VERSION 5.7 ;
  NOWIREEXTENSIONATPIN ON ;
  DIVIDERCHAR "/" ;
  BUSBITCHARS "[]" ;
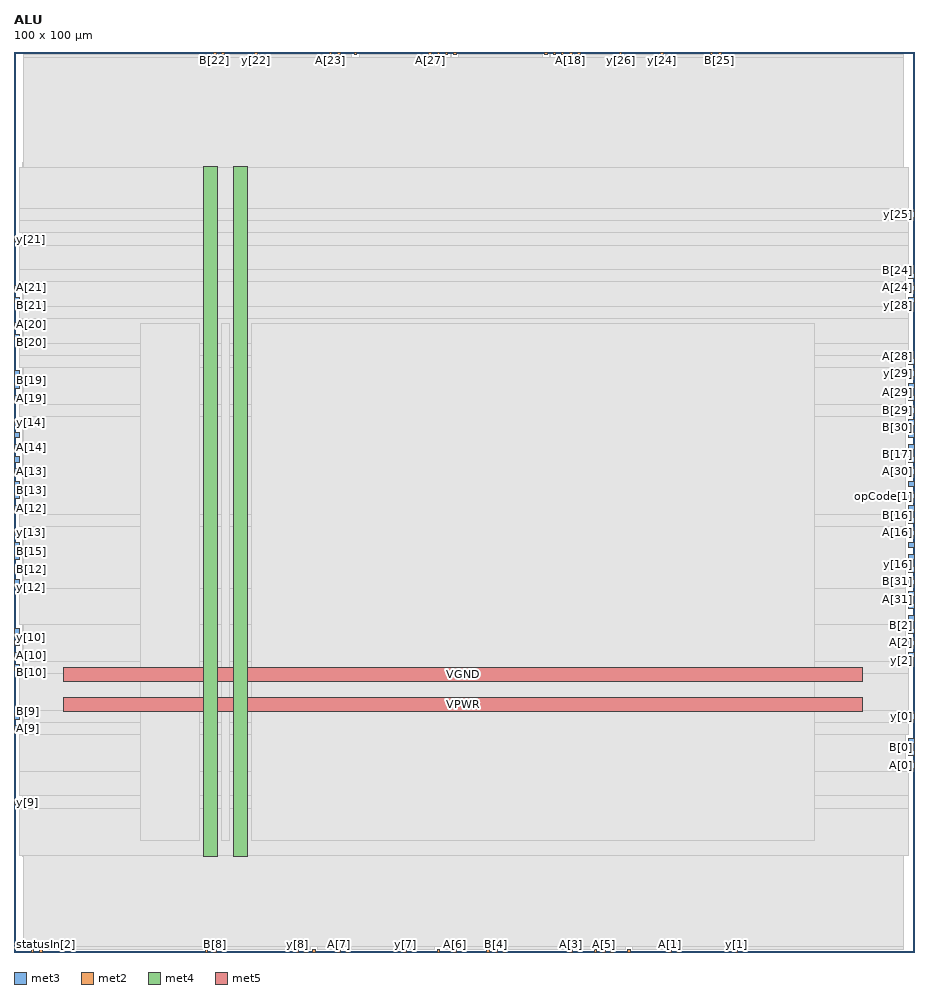
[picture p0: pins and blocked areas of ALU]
MACRO ALU
  CLASS BLOCK ;
  FOREIGN ALU ;
  ORIGIN 0.000 0.000 ;
  SIZE 100.000 BY 100.000 ;
  PIN A[0]
    DIRECTION INPUT ;
    USE SIGNAL ;
    ANTENNAGATEAREA 0.213000 ;
    PORT
      LAYER met3 ;
        RECT 99.400 20.440 100.000 21.040 ;
    END
  END A[0]
  PIN A[10]
    DIRECTION INPUT ;
    USE SIGNAL ;
    ANTENNAGATEAREA 0.213000 ;
    PORT
      LAYER met3 ;
        RECT 0.000 32.680 0.600 33.280 ;
    END
  END A[10]
  PIN A[11]
    DIRECTION INPUT ;
    USE SIGNAL ;
    ANTENNAGATEAREA 0.213000 ;
    PORT
      LAYER met2 ;
        RECT 32.290 0.000 32.570 0.280 ;
    END
  END A[11]
  PIN A[12]
    DIRECTION INPUT ;
    USE SIGNAL ;
    ANTENNAGATEAREA 0.213000 ;
    PORT
      LAYER met3 ;
        RECT 0.000 49.000 0.600 49.600 ;
    END
  END A[12]
  PIN A[13]
    DIRECTION INPUT ;
    USE SIGNAL ;
    ANTENNAGATEAREA 0.213000 ;
    PORT
      LAYER met3 ;
        RECT 0.000 53.080 0.600 53.680 ;
    END
  END A[13]
  PIN A[14]
    DIRECTION INPUT ;
    USE SIGNAL ;
    ANTENNAGATEAREA 0.213000 ;
    PORT
      LAYER met3 ;
        RECT 0.000 55.800 0.600 56.400 ;
    END
  END A[14]
  PIN A[15]
    DIRECTION INPUT ;
    USE SIGNAL ;
    ANTENNAGATEAREA 0.213000 ;
    PORT
      LAYER met3 ;
        RECT 0.000 44.920 0.600 45.520 ;
    END
  END A[15]
  PIN A[16]
    DIRECTION INPUT ;
    USE SIGNAL ;
    ANTENNAGATEAREA 0.213000 ;
    PORT
      LAYER met3 ;
        RECT 99.400 46.280 100.000 46.880 ;
    END
  END A[16]
  PIN A[17]
    DIRECTION INPUT ;
    USE SIGNAL ;
    ANTENNAGATEAREA 0.213000 ;
    PORT
      LAYER met3 ;
        RECT 99.400 57.160 100.000 57.760 ;
    END
  END A[17]
  PIN A[18]
    DIRECTION INPUT ;
    USE SIGNAL ;
    ANTENNAGATEAREA 0.213000 ;
    PORT
      LAYER met2 ;
        RECT 61.730 99.720 62.010 100.000 ;
    END
  END A[18]
  PIN A[19]
    DIRECTION INPUT ;
    USE SIGNAL ;
    ANTENNAGATEAREA 0.213000 ;
    PORT
      LAYER met3 ;
        RECT 0.000 61.240 0.600 61.840 ;
    END
  END A[19]
  PIN A[1]
    DIRECTION INPUT ;
    USE SIGNAL ;
    ANTENNAGATEAREA 0.213000 ;
    PORT
      LAYER met2 ;
        RECT 72.770 0.000 73.050 0.280 ;
    END
  END A[1]
  PIN A[20]
    DIRECTION INPUT ;
    USE SIGNAL ;
    ANTENNAGATEAREA 0.213000 ;
    PORT
      LAYER met3 ;
        RECT 0.000 69.400 0.600 70.000 ;
    END
  END A[20]
  PIN A[21]
    DIRECTION INPUT ;
    USE SIGNAL ;
    ANTENNAGATEAREA 0.213000 ;
    PORT
      LAYER met3 ;
        RECT 0.000 73.480 0.600 74.080 ;
    END
  END A[21]
  PIN A[22]
    DIRECTION INPUT ;
    USE SIGNAL ;
    ANTENNAGATEAREA 0.213000 ;
    PORT
      LAYER met2 ;
        RECT 23.090 99.720 23.370 100.000 ;
    END
  END A[22]
  PIN A[23]
    DIRECTION INPUT ;
    USE SIGNAL ;
    ANTENNAGATEAREA 0.213000 ;
    PORT
      LAYER met2 ;
        RECT 35.050 99.720 35.330 100.000 ;
    END
  END A[23]
  PIN A[24]
    DIRECTION INPUT ;
    USE SIGNAL ;
    ANTENNAGATEAREA 0.213000 ;
    PORT
      LAYER met3 ;
        RECT 99.400 73.480 100.000 74.080 ;
    END
  END A[24]
  PIN A[25]
    DIRECTION INPUT ;
    USE SIGNAL ;
    ANTENNAGATEAREA 0.213000 ;
    PORT
      LAYER met2 ;
        RECT 77.370 99.720 77.650 100.000 ;
    END
  END A[25]
  PIN A[26]
    DIRECTION INPUT ;
    USE SIGNAL ;
    ANTENNAGATEAREA 0.213000 ;
    PORT
      LAYER met2 ;
        RECT 58.970 99.720 59.250 100.000 ;
    END
  END A[26]
  PIN A[27]
    DIRECTION INPUT ;
    USE SIGNAL ;
    ANTENNAGATEAREA 0.213000 ;
    PORT
      LAYER met2 ;
        RECT 46.090 99.720 46.370 100.000 ;
    END
  END A[27]
  PIN A[28]
    DIRECTION INPUT ;
    USE SIGNAL ;
    ANTENNAGATEAREA 0.213000 ;
    PORT
      LAYER met3 ;
        RECT 99.400 65.320 100.000 65.920 ;
    END
  END A[28]
  PIN A[29]
    DIRECTION INPUT ;
    USE SIGNAL ;
    ANTENNAGATEAREA 0.213000 ;
    PORT
      LAYER met3 ;
        RECT 99.400 61.240 100.000 61.840 ;
    END
  END A[29]
  PIN A[2]
    DIRECTION INPUT ;
    USE SIGNAL ;
    ANTENNAGATEAREA 0.213000 ;
    PORT
      LAYER met3 ;
        RECT 99.400 34.040 100.000 34.640 ;
    END
  END A[2]
  PIN A[30]
    DIRECTION INPUT ;
    USE SIGNAL ;
    ANTENNAGATEAREA 0.213000 ;
    PORT
      LAYER met3 ;
        RECT 99.400 53.080 100.000 53.680 ;
    END
  END A[30]
  PIN A[31]
    DIRECTION INPUT ;
    USE SIGNAL ;
    ANTENNAGATEAREA 0.213000 ;
    PORT
      LAYER met3 ;
        RECT 99.400 39.480 100.000 40.080 ;
    END
  END A[31]
  PIN A[3]
    DIRECTION INPUT ;
    USE SIGNAL ;
    ANTENNAGATEAREA 0.213000 ;
    PORT
      LAYER met2 ;
        RECT 61.730 0.000 62.010 0.280 ;
    END
  END A[3]
  PIN A[4]
    DIRECTION INPUT ;
    USE SIGNAL ;
    ANTENNAGATEAREA 0.213000 ;
    PORT
      LAYER met2 ;
        RECT 52.530 0.000 52.810 0.280 ;
    END
  END A[4]
  PIN A[5]
    DIRECTION INPUT ;
    USE SIGNAL ;
    ANTENNAGATEAREA 0.213000 ;
    PORT
      LAYER met2 ;
        RECT 65.410 0.000 65.690 0.280 ;
    END
  END A[5]
  PIN A[6]
    DIRECTION INPUT ;
    USE SIGNAL ;
    ANTENNAGATEAREA 0.213000 ;
    PORT
      LAYER met2 ;
        RECT 48.850 0.000 49.130 0.280 ;
    END
  END A[6]
  PIN A[7]
    DIRECTION INPUT ;
    USE SIGNAL ;
    ANTENNAGATEAREA 0.213000 ;
    PORT
      LAYER met2 ;
        RECT 35.970 0.000 36.250 0.280 ;
    END
  END A[7]
  PIN A[8]
    DIRECTION INPUT ;
    USE SIGNAL ;
    ANTENNAGATEAREA 0.213000 ;
    PORT
      LAYER met2 ;
        RECT 21.250 0.000 21.530 0.280 ;
    END
  END A[8]
  PIN A[9]
    DIRECTION INPUT ;
    USE SIGNAL ;
    ANTENNAGATEAREA 0.213000 ;
    PORT
      LAYER met3 ;
        RECT 0.000 24.520 0.600 25.120 ;
    END
  END A[9]
  PIN B[0]
    DIRECTION INPUT ;
    USE SIGNAL ;
    ANTENNAGATEAREA 0.213000 ;
    PORT
      LAYER met3 ;
        RECT 99.400 21.800 100.000 22.400 ;
    END
  END B[0]
  PIN B[10]
    DIRECTION INPUT ;
    USE SIGNAL ;
    ANTENNAGATEAREA 0.213000 ;
    PORT
      LAYER met3 ;
        RECT 0.000 31.320 0.600 31.920 ;
    END
  END B[10]
  PIN B[11]
    DIRECTION INPUT ;
    USE SIGNAL ;
    ANTENNAGATEAREA 0.213000 ;
    PORT
      LAYER met2 ;
        RECT 33.210 0.000 33.490 0.280 ;
    END
  END B[11]
  PIN B[12]
    DIRECTION INPUT ;
    USE SIGNAL ;
    ANTENNAGATEAREA 0.213000 ;
    PORT
      LAYER met3 ;
        RECT 0.000 42.200 0.600 42.800 ;
    END
  END B[12]
  PIN B[13]
    DIRECTION INPUT ;
    USE SIGNAL ;
    ANTENNAGATEAREA 0.213000 ;
    PORT
      LAYER met3 ;
        RECT 0.000 50.360 0.600 50.960 ;
    END
  END B[13]
  PIN B[14]
    DIRECTION INPUT ;
    USE SIGNAL ;
    ANTENNAGATEAREA 0.213000 ;
    PORT
      LAYER met3 ;
        RECT 0.000 54.440 0.600 55.040 ;
    END
  END B[14]
  PIN B[15]
    DIRECTION INPUT ;
    USE SIGNAL ;
    ANTENNAGATEAREA 0.213000 ;
    PORT
      LAYER met3 ;
        RECT 0.000 43.560 0.600 44.160 ;
    END
  END B[15]
  PIN B[16]
    DIRECTION INPUT ;
    USE SIGNAL ;
    ANTENNAGATEAREA 0.213000 ;
    PORT
      LAYER met3 ;
        RECT 99.400 47.640 100.000 48.240 ;
    END
  END B[16]
  PIN B[17]
    DIRECTION INPUT ;
    USE SIGNAL ;
    ANTENNAGATEAREA 0.213000 ;
    PORT
      LAYER met3 ;
        RECT 99.400 54.440 100.000 55.040 ;
    END
  END B[17]
  PIN B[18]
    DIRECTION INPUT ;
    USE SIGNAL ;
    ANTENNAGATEAREA 0.213000 ;
    PORT
      LAYER met2 ;
        RECT 60.810 99.720 61.090 100.000 ;
    END
  END B[18]
  PIN B[19]
    DIRECTION INPUT ;
    USE SIGNAL ;
    ANTENNAGATEAREA 0.213000 ;
    PORT
      LAYER met3 ;
        RECT 0.000 62.600 0.600 63.200 ;
    END
  END B[19]
  PIN B[1]
    DIRECTION INPUT ;
    USE SIGNAL ;
    ANTENNAGATEAREA 0.213000 ;
    PORT
      LAYER met2 ;
        RECT 73.690 0.000 73.970 0.280 ;
    END
  END B[1]
  PIN B[20]
    DIRECTION INPUT ;
    USE SIGNAL ;
    ANTENNAGATEAREA 0.213000 ;
    PORT
      LAYER met3 ;
        RECT 0.000 68.040 0.600 68.640 ;
    END
  END B[20]
  PIN B[21]
    DIRECTION INPUT ;
    USE SIGNAL ;
    ANTENNAGATEAREA 0.213000 ;
    PORT
      LAYER met3 ;
        RECT 0.000 72.120 0.600 72.720 ;
    END
  END B[21]
  PIN B[22]
    DIRECTION INPUT ;
    USE SIGNAL ;
    ANTENNAGATEAREA 0.213000 ;
    PORT
      LAYER met2 ;
        RECT 22.170 99.720 22.450 100.000 ;
    END
  END B[22]
  PIN B[23]
    DIRECTION INPUT ;
    USE SIGNAL ;
    ANTENNAGATEAREA 0.213000 ;
    PORT
      LAYER met2 ;
        RECT 35.970 99.720 36.250 100.000 ;
    END
  END B[23]
  PIN B[24]
    DIRECTION INPUT ;
    USE SIGNAL ;
    ANTENNAGATEAREA 0.213000 ;
    PORT
      LAYER met3 ;
        RECT 99.400 74.840 100.000 75.440 ;
    END
  END B[24]
  PIN B[25]
    DIRECTION INPUT ;
    USE SIGNAL ;
    ANTENNAGATEAREA 0.213000 ;
    PORT
      LAYER met2 ;
        RECT 78.290 99.720 78.570 100.000 ;
    END
  END B[25]
  PIN B[26]
    DIRECTION INPUT ;
    USE SIGNAL ;
    ANTENNAGATEAREA 0.213000 ;
    PORT
      LAYER met2 ;
        RECT 59.890 99.720 60.170 100.000 ;
    END
  END B[26]
  PIN B[27]
    DIRECTION INPUT ;
    USE SIGNAL ;
    ANTENNAGATEAREA 0.213000 ;
    PORT
      LAYER met2 ;
        RECT 47.010 99.720 47.290 100.000 ;
    END
  END B[27]
  PIN B[28]
    DIRECTION INPUT ;
    USE SIGNAL ;
    ANTENNAGATEAREA 0.213000 ;
    PORT
      LAYER met3 ;
        RECT 99.400 62.600 100.000 63.200 ;
    END
  END B[28]
  PIN B[29]
    DIRECTION INPUT ;
    USE SIGNAL ;
    ANTENNAGATEAREA 0.213000 ;
    PORT
      LAYER met3 ;
        RECT 99.400 59.880 100.000 60.480 ;
    END
  END B[29]
  PIN B[2]
    DIRECTION INPUT ;
    USE SIGNAL ;
    ANTENNAGATEAREA 0.213000 ;
    PORT
      LAYER met3 ;
        RECT 99.400 35.400 100.000 36.000 ;
    END
  END B[2]
  PIN B[30]
    DIRECTION INPUT ;
    USE SIGNAL ;
    ANTENNAGATEAREA 0.213000 ;
    PORT
      LAYER met3 ;
        RECT 99.400 58.520 100.000 59.120 ;
    END
  END B[30]
  PIN B[31]
    DIRECTION INPUT ;
    USE SIGNAL ;
    ANTENNAGATEAREA 0.213000 ;
    PORT
      LAYER met3 ;
        RECT 99.400 40.840 100.000 41.440 ;
    END
  END B[31]
  PIN B[3]
    DIRECTION INPUT ;
    USE SIGNAL ;
    ANTENNAGATEAREA 0.213000 ;
    PORT
      LAYER met3 ;
        RECT 99.400 36.760 100.000 37.360 ;
    END
  END B[3]
  PIN B[4]
    DIRECTION INPUT ;
    USE SIGNAL ;
    ANTENNAGATEAREA 0.213000 ;
    PORT
      LAYER met2 ;
        RECT 53.450 0.000 53.730 0.280 ;
    END
  END B[4]
  PIN B[5]
    DIRECTION INPUT ;
    USE SIGNAL ;
    ANTENNAGATEAREA 0.213000 ;
    PORT
      LAYER met2 ;
        RECT 66.330 0.000 66.610 0.280 ;
    END
  END B[5]
  PIN B[6]
    DIRECTION INPUT ;
    USE SIGNAL ;
    ANTENNAGATEAREA 0.213000 ;
    PORT
      LAYER met2 ;
        RECT 47.010 0.000 47.290 0.280 ;
    END
  END B[6]
  PIN B[7]
    DIRECTION INPUT ;
    USE SIGNAL ;
    ANTENNAGATEAREA 0.213000 ;
    PORT
      LAYER met2 ;
        RECT 36.890 0.000 37.170 0.280 ;
    END
  END B[7]
  PIN B[8]
    DIRECTION INPUT ;
    USE SIGNAL ;
    ANTENNAGATEAREA 0.213000 ;
    PORT
      LAYER met2 ;
        RECT 22.170 0.000 22.450 0.280 ;
    END
  END B[8]
  PIN B[9]
    DIRECTION INPUT ;
    USE SIGNAL ;
    ANTENNAGATEAREA 0.213000 ;
    PORT
      LAYER met3 ;
        RECT 0.000 25.880 0.600 26.480 ;
    END
  END B[9]
  PIN VGND
    DIRECTION INOUT ;
    USE GROUND ;
    PORT
      LAYER met4 ;
        RECT 24.340 10.640 25.940 87.280 ;
    END
    PORT
      LAYER met5 ;
        RECT 5.520 30.030 94.300 31.630 ;
    END
  END VGND
  PIN VPWR
    DIRECTION INOUT ;
    USE POWER ;
    PORT
      LAYER met4 ;
        RECT 21.040 10.640 22.640 87.280 ;
    END
    PORT
      LAYER met5 ;
        RECT 5.520 26.730 94.300 28.330 ;
    END
  END VPWR
  PIN opCode[0]
    DIRECTION INPUT ;
    USE SIGNAL ;
    ANTENNAGATEAREA 0.213000 ;
    PORT
      LAYER met3 ;
        RECT 99.400 49.000 100.000 49.600 ;
    END
  END opCode[0]
  PIN opCode[1]
    DIRECTION INPUT ;
    USE SIGNAL ;
    ANTENNAGATEAREA 0.213000 ;
    PORT
      LAYER met3 ;
        RECT 99.400 50.360 100.000 50.960 ;
    END
  END opCode[1]
  PIN opCode[2]
    DIRECTION INPUT ;
    USE SIGNAL ;
    ANTENNAGATEAREA 0.213000 ;
    PORT
      LAYER met3 ;
        RECT 99.400 51.720 100.000 52.320 ;
    END
  END opCode[2]
  PIN statusIn[0]
    DIRECTION INPUT ;
    USE SIGNAL ;
    ANTENNAGATEAREA 0.213000 ;
    PORT
      LAYER met3 ;
        RECT 99.400 23.160 100.000 23.760 ;
    END
  END statusIn[0]
  PIN statusIn[1]
    DIRECTION INPUT ;
    USE SIGNAL ;
    PORT
      LAYER met2 ;
        RECT 1.930 0.000 2.210 0.280 ;
    END
  END statusIn[1]
  PIN statusIn[2]
    DIRECTION INPUT ;
    USE SIGNAL ;
    PORT
      LAYER met2 ;
        RECT 2.850 0.000 3.130 0.280 ;
    END
  END statusIn[2]
  PIN statusOut
    DIRECTION OUTPUT ;
    USE SIGNAL ;
    ANTENNADIFFAREA 0.702900 ;
    PORT
      LAYER met3 ;
        RECT 99.400 44.920 100.000 45.520 ;
    END
  END statusOut
  PIN y[0]
    DIRECTION OUTPUT ;
    USE SIGNAL ;
    ANTENNADIFFAREA 0.702900 ;
    PORT
      LAYER met3 ;
        RECT 99.400 25.880 100.000 26.480 ;
    END
  END y[0]
  PIN y[10]
    DIRECTION OUTPUT ;
    USE SIGNAL ;
    ANTENNADIFFAREA 0.702900 ;
    PORT
      LAYER met3 ;
        RECT 0.000 34.040 0.600 34.640 ;
    END
  END y[10]
  PIN y[11]
    DIRECTION OUTPUT ;
    USE SIGNAL ;
    ANTENNADIFFAREA 0.702900 ;
    PORT
      LAYER met3 ;
        RECT 0.000 35.400 0.600 36.000 ;
    END
  END y[11]
  PIN y[12]
    DIRECTION OUTPUT ;
    USE SIGNAL ;
    ANTENNADIFFAREA 0.702900 ;
    PORT
      LAYER met3 ;
        RECT 0.000 40.840 0.600 41.440 ;
    END
  END y[12]
  PIN y[13]
    DIRECTION OUTPUT ;
    USE SIGNAL ;
    ANTENNADIFFAREA 0.702900 ;
    PORT
      LAYER met3 ;
        RECT 0.000 46.280 0.600 46.880 ;
    END
  END y[13]
  PIN y[14]
    DIRECTION OUTPUT ;
    USE SIGNAL ;
    ANTENNADIFFAREA 0.702900 ;
    PORT
      LAYER met3 ;
        RECT 0.000 58.520 0.600 59.120 ;
    END
  END y[14]
  PIN y[15]
    DIRECTION OUTPUT ;
    USE SIGNAL ;
    ANTENNADIFFAREA 0.702900 ;
    PORT
      LAYER met3 ;
        RECT 0.000 51.720 0.600 52.320 ;
    END
  END y[15]
  PIN y[16]
    DIRECTION OUTPUT ;
    USE SIGNAL ;
    ANTENNADIFFAREA 0.702900 ;
    PORT
      LAYER met3 ;
        RECT 99.400 42.200 100.000 42.800 ;
    END
  END y[16]
  PIN y[17]
    DIRECTION OUTPUT ;
    USE SIGNAL ;
    ANTENNADIFFAREA 0.702900 ;
    PORT
      LAYER met2 ;
        RECT 48.850 99.720 49.130 100.000 ;
    END
  END y[17]
  PIN y[18]
    DIRECTION OUTPUT ;
    USE SIGNAL ;
    ANTENNADIFFAREA 0.702900 ;
    PORT
      LAYER met2 ;
        RECT 62.650 99.720 62.930 100.000 ;
    END
  END y[18]
  PIN y[19]
    DIRECTION OUTPUT ;
    USE SIGNAL ;
    ANTENNADIFFAREA 0.702900 ;
    PORT
      LAYER met3 ;
        RECT 0.000 57.160 0.600 57.760 ;
    END
  END y[19]
  PIN y[1]
    DIRECTION OUTPUT ;
    USE SIGNAL ;
    ANTENNADIFFAREA 0.702900 ;
    PORT
      LAYER met2 ;
        RECT 80.130 0.000 80.410 0.280 ;
    END
  END y[1]
  PIN y[20]
    DIRECTION OUTPUT ;
    USE SIGNAL ;
    ANTENNADIFFAREA 0.702900 ;
    PORT
      LAYER met3 ;
        RECT 0.000 63.960 0.600 64.560 ;
    END
  END y[20]
  PIN y[21]
    DIRECTION OUTPUT ;
    USE SIGNAL ;
    ANTENNADIFFAREA 0.702900 ;
    PORT
      LAYER met3 ;
        RECT 0.000 78.920 0.600 79.520 ;
    END
  END y[21]
  PIN y[22]
    DIRECTION OUTPUT ;
    USE SIGNAL ;
    ANTENNADIFFAREA 0.702900 ;
    PORT
      LAYER met2 ;
        RECT 26.770 99.720 27.050 100.000 ;
    END
  END y[22]
  PIN y[23]
    DIRECTION OUTPUT ;
    USE SIGNAL ;
    ANTENNADIFFAREA 0.702900 ;
    PORT
      LAYER met2 ;
        RECT 37.810 99.720 38.090 100.000 ;
    END
  END y[23]
  PIN y[24]
    DIRECTION OUTPUT ;
    USE SIGNAL ;
    ANTENNADIFFAREA 0.702900 ;
    PORT
      LAYER met2 ;
        RECT 71.850 99.720 72.130 100.000 ;
    END
  END y[24]
  PIN y[25]
    DIRECTION OUTPUT ;
    USE SIGNAL ;
    ANTENNADIFFAREA 0.702900 ;
    PORT
      LAYER met3 ;
        RECT 99.400 81.640 100.000 82.240 ;
    END
  END y[25]
  PIN y[26]
    DIRECTION OUTPUT ;
    USE SIGNAL ;
    ANTENNADIFFAREA 0.702900 ;
    PORT
      LAYER met2 ;
        RECT 67.250 99.720 67.530 100.000 ;
    END
  END y[26]
  PIN y[27]
    DIRECTION OUTPUT ;
    USE SIGNAL ;
    ANTENNADIFFAREA 0.702900 ;
    PORT
      LAYER met2 ;
        RECT 47.930 99.720 48.210 100.000 ;
    END
  END y[27]
  PIN y[28]
    DIRECTION OUTPUT ;
    USE SIGNAL ;
    ANTENNADIFFAREA 0.702900 ;
    PORT
      LAYER met3 ;
        RECT 99.400 72.120 100.000 72.720 ;
    END
  END y[28]
  PIN y[29]
    DIRECTION OUTPUT ;
    USE SIGNAL ;
    ANTENNADIFFAREA 0.702900 ;
    PORT
      LAYER met3 ;
        RECT 99.400 63.960 100.000 64.560 ;
    END
  END y[29]
  PIN y[2]
    DIRECTION OUTPUT ;
    USE SIGNAL ;
    ANTENNADIFFAREA 0.702900 ;
    PORT
      LAYER met3 ;
        RECT 99.400 32.680 100.000 33.280 ;
    END
  END y[2]
  PIN y[30]
    DIRECTION OUTPUT ;
    USE SIGNAL ;
    ANTENNADIFFAREA 0.702900 ;
    PORT
      LAYER met3 ;
        RECT 99.400 55.800 100.000 56.400 ;
    END
  END y[30]
  PIN y[31]
    DIRECTION OUTPUT ;
    USE SIGNAL ;
    ANTENNADIFFAREA 0.702900 ;
    PORT
      LAYER met3 ;
        RECT 99.400 43.560 100.000 44.160 ;
    END
  END y[31]
  PIN y[3]
    DIRECTION OUTPUT ;
    USE SIGNAL ;
    ANTENNADIFFAREA 0.702900 ;
    PORT
      LAYER met3 ;
        RECT 99.400 38.120 100.000 38.720 ;
    END
  END y[3]
  PIN y[4]
    DIRECTION OUTPUT ;
    USE SIGNAL ;
    ANTENNADIFFAREA 0.702900 ;
    PORT
      LAYER met2 ;
        RECT 54.370 0.000 54.650 0.280 ;
    END
  END y[4]
  PIN y[5]
    DIRECTION OUTPUT ;
    USE SIGNAL ;
    ANTENNADIFFAREA 0.702900 ;
    PORT
      LAYER met2 ;
        RECT 68.170 0.000 68.450 0.280 ;
    END
  END y[5]
  PIN y[6]
    DIRECTION OUTPUT ;
    USE SIGNAL ;
    ANTENNADIFFAREA 0.702900 ;
    PORT
      LAYER met2 ;
        RECT 64.490 0.000 64.770 0.280 ;
    END
  END y[6]
  PIN y[7]
    DIRECTION OUTPUT ;
    USE SIGNAL ;
    ANTENNADIFFAREA 0.702900 ;
    PORT
      LAYER met2 ;
        RECT 43.330 0.000 43.610 0.280 ;
    END
  END y[7]
  PIN y[8]
    DIRECTION OUTPUT ;
    USE SIGNAL ;
    ANTENNADIFFAREA 0.702900 ;
    PORT
      LAYER met2 ;
        RECT 31.370 0.000 31.650 0.280 ;
    END
  END y[8]
  PIN y[9]
    DIRECTION OUTPUT ;
    USE SIGNAL ;
    ANTENNADIFFAREA 0.702900 ;
    PORT
      LAYER met3 ;
        RECT 0.000 16.360 0.600 16.960 ;
    END
  END y[9]
  OBS
      LAYER nwell ;
        RECT 5.330 10.795 94.490 87.125 ;
      LAYER li1 ;
        RECT 5.520 10.795 94.300 87.125 ;
      LAYER met1 ;
        RECT 0.990 10.640 98.830 87.680 ;
      LAYER met2 ;
        RECT 1.010 99.440 21.890 99.720 ;
        RECT 22.730 99.440 22.810 99.720 ;
        RECT 23.650 99.440 26.490 99.720 ;
        RECT 27.330 99.440 34.770 99.720 ;
        RECT 35.610 99.440 35.690 99.720 ;
        RECT 36.530 99.440 37.530 99.720 ;
        RECT 38.370 99.440 45.810 99.720 ;
        RECT 46.650 99.440 46.730 99.720 ;
        RECT 47.570 99.440 47.650 99.720 ;
        RECT 48.490 99.440 48.570 99.720 ;
        RECT 49.410 99.440 58.690 99.720 ;
        RECT 59.530 99.440 59.610 99.720 ;
        RECT 60.450 99.440 60.530 99.720 ;
        RECT 61.370 99.440 61.450 99.720 ;
        RECT 62.290 99.440 62.370 99.720 ;
        RECT 63.210 99.440 66.970 99.720 ;
        RECT 67.810 99.440 71.570 99.720 ;
        RECT 72.410 99.440 77.090 99.720 ;
        RECT 77.930 99.440 78.010 99.720 ;
        RECT 78.850 99.440 98.810 99.720 ;
        RECT 1.010 0.560 98.810 99.440 ;
        RECT 1.010 0.280 1.650 0.560 ;
        RECT 2.490 0.280 2.570 0.560 ;
        RECT 3.410 0.280 20.970 0.560 ;
        RECT 21.810 0.280 21.890 0.560 ;
        RECT 22.730 0.280 31.090 0.560 ;
        RECT 31.930 0.280 32.010 0.560 ;
        RECT 32.850 0.280 32.930 0.560 ;
        RECT 33.770 0.280 35.690 0.560 ;
        RECT 36.530 0.280 36.610 0.560 ;
        RECT 37.450 0.280 43.050 0.560 ;
        RECT 43.890 0.280 46.730 0.560 ;
        RECT 47.570 0.280 48.570 0.560 ;
        RECT 49.410 0.280 52.250 0.560 ;
        RECT 53.090 0.280 53.170 0.560 ;
        RECT 54.010 0.280 54.090 0.560 ;
        RECT 54.930 0.280 61.450 0.560 ;
        RECT 62.290 0.280 64.210 0.560 ;
        RECT 65.050 0.280 65.130 0.560 ;
        RECT 65.970 0.280 66.050 0.560 ;
        RECT 66.890 0.280 67.890 0.560 ;
        RECT 68.730 0.280 72.490 0.560 ;
        RECT 73.330 0.280 73.410 0.560 ;
        RECT 74.250 0.280 79.850 0.560 ;
        RECT 80.690 0.280 98.810 0.560 ;
      LAYER met3 ;
        RECT 0.600 82.640 99.400 87.205 ;
        RECT 0.600 81.240 99.000 82.640 ;
        RECT 0.600 79.920 99.400 81.240 ;
        RECT 1.000 78.520 99.400 79.920 ;
        RECT 0.600 75.840 99.400 78.520 ;
        RECT 0.600 74.480 99.000 75.840 ;
        RECT 1.000 71.720 99.000 74.480 ;
        RECT 0.600 70.400 99.400 71.720 ;
        RECT 1.000 67.640 99.400 70.400 ;
        RECT 0.600 66.320 99.400 67.640 ;
        RECT 0.600 64.960 99.000 66.320 ;
        RECT 1.000 60.840 99.000 64.960 ;
        RECT 0.600 59.520 99.000 60.840 ;
        RECT 1.000 48.600 99.000 59.520 ;
        RECT 0.600 47.280 99.000 48.600 ;
        RECT 1.000 40.440 99.000 47.280 ;
        RECT 0.600 36.400 99.000 40.440 ;
        RECT 1.000 32.280 99.000 36.400 ;
        RECT 1.000 30.920 99.400 32.280 ;
        RECT 0.600 26.880 99.400 30.920 ;
        RECT 1.000 25.480 99.000 26.880 ;
        RECT 1.000 24.160 99.400 25.480 ;
        RECT 1.000 24.120 99.000 24.160 ;
        RECT 0.600 20.040 99.000 24.120 ;
        RECT 0.600 17.360 99.400 20.040 ;
        RECT 1.000 15.960 99.400 17.360 ;
        RECT 0.600 10.715 99.400 15.960 ;
      LAYER met4 ;
        RECT 14.095 12.415 20.640 69.865 ;
        RECT 23.040 12.415 23.940 69.865 ;
        RECT 26.340 12.415 88.945 69.865 ;
  END
END ALU
END LIBRARY

